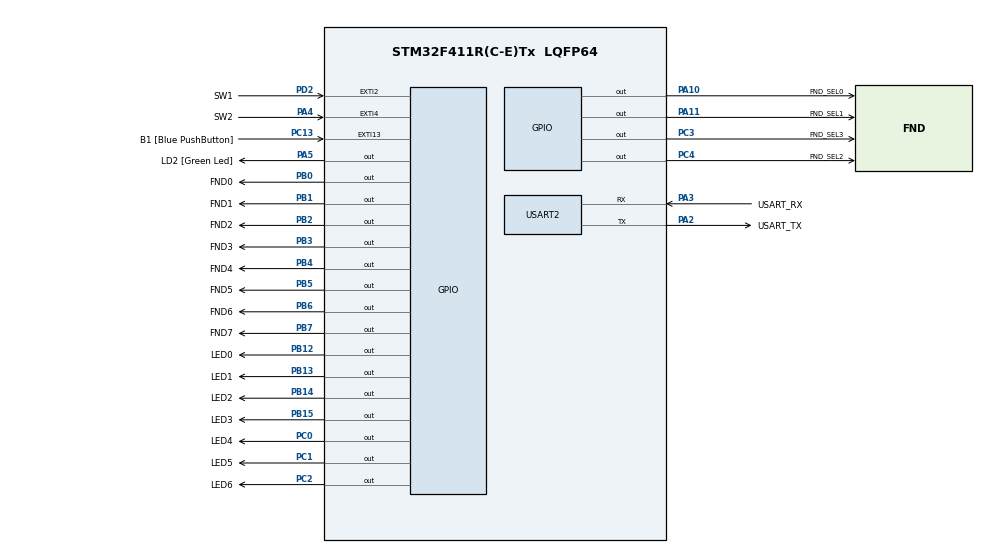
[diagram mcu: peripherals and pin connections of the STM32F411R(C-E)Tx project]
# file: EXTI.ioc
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Mcu.Family=STM32F4
Mcu.Name=STM32F411R(C-E)Tx
Mcu.Package=LQFP64
NVIC.EXTI15_10_IRQn=true\:0\:0\:false\:false\:true\:true\:true\:true
NVIC.EXTI2_IRQn=true\:0\:0\:false\:false\:true\:true\:true\:true
NVIC.EXTI4_IRQn=true\:0\:0\:false\:false\:true\:true\:true\:true
NVIC.PriorityGroup=NVIC_PRIORITYGROUP_0
PA10.GPIO_Label=FND_SEL0
PA10.Signal=GPIO_Output
PA11.GPIO_Label=FND_SEL1
PA11.Signal=GPIO_Output
PA13.GPIO_Label=TMS
PA13.Mode=Serial_Wire
PA13.Signal=SYS_JTMS-SWDIO
PA14.GPIO_Label=TCK
PA14.Mode=Serial_Wire
PA14.Signal=SYS_JTCK-SWCLK
PA2.GPIO_Label=USART_TX
PA2.Mode=Asynchronous
PA2.Signal=USART2_TX
PA3.GPIO_Label=USART_RX
PA3.Mode=Asynchronous
PA3.Signal=USART2_RX
PA4.GPIO_Label=SW2
PA4.Signal=GPXTI4
PA5.GPIO_Label=LD2 [Green Led]
PA5.Signal=GPIO_Output
PB0.GPIO_Label=FND0
PB0.Signal=GPIO_Output
PB1.GPIO_Label=FND1
PB1.Signal=GPIO_Output
PB12.GPIO_Label=LED0
PB12.Signal=GPIO_Output
PB13.GPIO_Label=LED1
PB13.Signal=GPIO_Output
PB14.GPIO_Label=LED2
PB14.Signal=GPIO_Output
PB15.GPIO_Label=LED3
PB15.Signal=GPIO_Output
PB2.GPIO_Label=FND2
PB2.Signal=GPIO_Output
PB3.GPIO_Label=FND3
PB3.Signal=GPIO_Output
PB4.GPIO_Label=FND4
PB4.Signal=GPIO_Output
PB5.GPIO_Label=FND5
PB5.Signal=GPIO_Output
PB6.GPIO_Label=FND6
PB6.Signal=GPIO_Output
PB7.GPIO_Label=FND7
PB7.Signal=GPIO_Output
PC0.GPIO_Label=LED4
PC0.Signal=GPIO_Output
PC1.GPIO_Label=LED5
PC1.Signal=GPIO_Output
PC13-ANTI_TAMP.GPIO_Label=B1 [Blue PushButton]
PC13-ANTI_TAMP.GPIO_ModeDefaultEXTI=GPIO_MODE_IT_RISING_FALLING
PC13-ANTI_TAMP.Signal=GPXTI13
PC14-OSC32_IN.Signal=RCC_OSC32_IN
PC15-OSC32_OUT.Signal=RCC_OSC32_OUT
PC2.GPIO_Label=LED6
PC2.Signal=GPIO_Output
PC3.GPIO_Label=FND_SEL3
PC3.Signal=GPIO_Output
PC4.GPIO_Label=FND_SEL2
PC4.Signal=GPIO_Output
PD2.GPIO_Label=SW1
PD2.GPIO_ModeDefaultEXTI=GPIO_MODE_IT_RISING_FALLING
PD2.Signal=GPXTI2
PH0\ -\ OSC_IN.Signal=RCC_OSC_IN
PH1\ -\ OSC_OUT.Signal=RCC_OSC_OUT
ProjectManager.HeapSize=0x200
ProjectManager.StackSize=0x400
ProjectManager.TargetToolchain=STM32CubeIDE
RCC.48MHZClocksFreq_Value=32000000
RCC.AHBFreq_Value=64000000
RCC.APB1CLKDivider=RCC_HCLK_DIV2
RCC.APB1Freq_Value=32000000
RCC.APB1TimFreq_Value=64000000
RCC.APB2Freq_Value=64000000
RCC.APB2TimFreq_Value=64000000
RCC.CortexFreq_Value=64000000
RCC.FLatency-AdvancedSettings=FLASH_LATENCY_2
RCC.HCLKFreq_Value=64000000
RCC.HSE_VALUE=8000000
RCC.HSI_VALUE=16000000
RCC.PLLM=8
RCC.PLLN=64
RCC.SYSCLKFreq_VALUE=64000000
RCC.SYSCLKSource=RCC_SYSCLKSOURCE_PLLCLK
RCC.VCOOutputFreq_Value=128000000
USART2.VirtualMode=VM_ASYNC
board=NUCLEO-F411RE

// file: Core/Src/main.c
/* USER CODE BEGIN Header */
/**
  ******************************************************************************
  * @file           : main.c
  * @brief          : Main program body
  ******************************************************************************
  * @attention
  *
  * Copyright (c) 2023 STMicroelectronics.
  * All rights reserved.
  *
  * This software is licensed under terms that can be found in the LICENSE file
  * in the root directory of this software component.
  * If no LICENSE file comes with this software, it is provided AS-IS.
  *
  ******************************************************************************
  */
/* USER CODE END Header */
#include "main.h"

UART_HandleTypeDef huart2;

/* USER CODE BEGIN PV */
int i=0, icnt, SW1Flag, SW2Flag;
uint16_t data[4] = {1,2,3,4}, _digit=0;

/* USER CODE END PV */

void SystemClock_Config(void);
static void MX_GPIO_Init(void);
static void MX_USART2_UART_Init(void);
/* USER CODE BEGIN PFP */
void Seg_Reset(void);
void Seg_Number(uint16_t val, uint8_t dp);
/* USER CODE END PFP */

int main(void)
{

  /* MCU Configuration--------------------------------------------------------*/

  /* Reset of all peripherals, Initializes the Flash interface and the Systick. */
  HAL_Init();

  /* Configure the system clock */
  SystemClock_Config();

  /* Initialize all configured peripherals */
  MX_GPIO_Init();
  MX_USART2_UART_Init();

  /* Infinite loop */
  /* USER CODE BEGIN WHILE */
  icnt=0;

  SW1Flag=0;
  SW2Flag=0;

  _digit=0;
  Seg_Reset();

  while (1)
  {

     HAL_GPIO_WritePin(GPIOA, FND_SEL0_Pin, GPIO_PIN_SET);

  if( _digit == 0)

     Seg_Number(data[0],1);

  else

     Seg_Number(data[0],0);

  HAL_Delay(5);

  HAL_GPIO_WritePin(GPIOA, FND_SEL0_Pin, GPIO_PIN_RESET);

  HAL_GPIO_WritePin(GPIOA, FND_SEL1_Pin, GPIO_PIN_SET);

  if( _digit == 1)

     Seg_Number(data[1],1);

  else

       Seg_Number(data[1],0);

  HAL_Delay(5);

  HAL_GPIO_WritePin(GPIOA, FND_SEL1_Pin, GPIO_PIN_RESET);

  HAL_GPIO_WritePin(GPIOC, FND_SEL2_Pin, GPIO_PIN_SET);

  if( _digit == 2)

     Seg_Number(data[2],1);

  else

       Seg_Number(data[2],0);

  HAL_Delay(5);

  HAL_GPIO_WritePin(GPIOC, FND_SEL2_Pin, GPIO_PIN_RESET);

  HAL_GPIO_WritePin(GPIOC, FND_SEL3_Pin, GPIO_PIN_SET);

  if( _digit == 3)

        Seg_Number(data[3],1);

     else

          Seg_Number(data[3],0);

       HAL_Delay(5);

       HAL_GPIO_WritePin(GPIOC, FND_SEL3_Pin, GPIO_PIN_RESET);

     if( SW1Flag ){

              SW1Flag=0;

              data[_digit]++;

              data[_digit] %= 10;

           }

           if(SW2Flag){

              SW2Flag=0;

              _digit++;

              _digit %= 4;

           }
    /* USER CODE END WHILE */

  }
}

void SystemClock_Config(void)
{
  RCC_OscInitTypeDef RCC_OscInitStruct = {0};
  RCC_ClkInitTypeDef RCC_ClkInitStruct = {0};

  /** Configure the main internal regulator output voltage
  */
  __HAL_RCC_PWR_CLK_ENABLE();
  __HAL_PWR_VOLTAGESCALING_CONFIG(PWR_REGULATOR_VOLTAGE_SCALE1);

  /** Initializes the RCC Oscillators according to the specified parameters
  * in the RCC_OscInitTypeDef structure.
  */
  RCC_OscInitStruct.OscillatorType = RCC_OSCILLATORTYPE_HSI;
  RCC_OscInitStruct.HSIState = RCC_HSI_ON;
  RCC_OscInitStruct.HSICalibrationValue = RCC_HSICALIBRATION_DEFAULT;
  RCC_OscInitStruct.PLL.PLLState = RCC_PLL_ON;
  RCC_OscInitStruct.PLL.PLLSource = RCC_PLLSOURCE_HSI;
  RCC_OscInitStruct.PLL.PLLM = 16;
  RCC_OscInitStruct.PLL.PLLN = 336;
  RCC_OscInitStruct.PLL.PLLP = RCC_PLLP_DIV4;
  RCC_OscInitStruct.PLL.PLLQ = 4;
  if (HAL_RCC_OscConfig(&RCC_OscInitStruct) != HAL_OK)
  {
    Error_Handler();
  }

  /** Initializes the CPU, AHB and APB buses clocks
  */
  RCC_ClkInitStruct.ClockType = RCC_CLOCKTYPE_HCLK|RCC_CLOCKTYPE_SYSCLK
                              |RCC_CLOCKTYPE_PCLK1|RCC_CLOCKTYPE_PCLK2;
  RCC_ClkInitStruct.SYSCLKSource = RCC_SYSCLKSOURCE_PLLCLK;
  RCC_ClkInitStruct.AHBCLKDivider = RCC_SYSCLK_DIV1;
  RCC_ClkInitStruct.APB1CLKDivider = RCC_HCLK_DIV2;
  RCC_ClkInitStruct.APB2CLKDivider = RCC_HCLK_DIV1;

  if (HAL_RCC_ClockConfig(&RCC_ClkInitStruct, FLASH_LATENCY_2) != HAL_OK)
  {
    Error_Handler();
  }
}

static void MX_USART2_UART_Init(void)
{

  huart2.Instance = USART2;
  huart2.Init.BaudRate = 115200;
  huart2.Init.WordLength = UART_WORDLENGTH_8B;
  huart2.Init.StopBits = UART_STOPBITS_1;
  huart2.Init.Parity = UART_PARITY_NONE;
  huart2.Init.Mode = UART_MODE_TX_RX;
  huart2.Init.HwFlowCtl = UART_HWCONTROL_NONE;
  huart2.Init.OverSampling = UART_OVERSAMPLING_16;
  if (HAL_UART_Init(&huart2) != HAL_OK)
  {
    Error_Handler();
  }

}

static void MX_GPIO_Init(void)
{
  GPIO_InitTypeDef GPIO_InitStruct = {0};

  /* GPIO Ports Clock Enable */
  __HAL_RCC_GPIOC_CLK_ENABLE();
  __HAL_RCC_GPIOH_CLK_ENABLE();
  __HAL_RCC_GPIOA_CLK_ENABLE();
  __HAL_RCC_GPIOB_CLK_ENABLE();
  __HAL_RCC_GPIOD_CLK_ENABLE();

  /*Configure GPIO pin Output Level */
  HAL_GPIO_WritePin(GPIOC, LED4_Pin|LED5_Pin|LED6_Pin|FND_SEL3_Pin
                          |FND_SEL2_Pin, GPIO_PIN_RESET);

  /*Configure GPIO pin Output Level */
  HAL_GPIO_WritePin(GPIOA, LD2_Pin|FND_SEL0_Pin|FND_SEL1_Pin, GPIO_PIN_RESET);

  /*Configure GPIO pin Output Level */
  HAL_GPIO_WritePin(GPIOB, FND0_Pin|FND1_Pin|FND2_Pin|LED0_Pin
                          |LED1_Pin|LED2_Pin|LED3_Pin|FND3_Pin
                          |FND4_Pin|FND5_Pin|FND6_Pin|FND7_Pin, GPIO_PIN_RESET);

  /*Configure GPIO pin : B1_Pin */
  GPIO_InitStruct.Pin = B1_Pin;
  GPIO_InitStruct.Mode = GPIO_MODE_IT_FALLING;
  GPIO_InitStruct.Pull = GPIO_NOPULL;
  HAL_GPIO_Init(B1_GPIO_Port, &GPIO_InitStruct);

  /*Configure GPIO pins : LED4_Pin LED5_Pin LED6_Pin FND_SEL3_Pin
                           FND_SEL2_Pin */
  GPIO_InitStruct.Pin = LED4_Pin|LED5_Pin|LED6_Pin|FND_SEL3_Pin
                          |FND_SEL2_Pin;
  GPIO_InitStruct.Mode = GPIO_MODE_OUTPUT_PP;
  GPIO_InitStruct.Pull = GPIO_NOPULL;
  GPIO_InitStruct.Speed = GPIO_SPEED_FREQ_LOW;
  HAL_GPIO_Init(GPIOC, &GPIO_InitStruct);

  /*Configure GPIO pin : SW2_Pin */
  GPIO_InitStruct.Pin = SW2_Pin;
  GPIO_InitStruct.Mode = GPIO_MODE_IT_RISING;
  GPIO_InitStruct.Pull = GPIO_NOPULL;
  HAL_GPIO_Init(SW2_GPIO_Port, &GPIO_InitStruct);

  /*Configure GPIO pins : LD2_Pin FND_SEL0_Pin FND_SEL1_Pin */
  GPIO_InitStruct.Pin = LD2_Pin|FND_SEL0_Pin|FND_SEL1_Pin;
  GPIO_InitStruct.Mode = GPIO_MODE_OUTPUT_PP;
  GPIO_InitStruct.Pull = GPIO_NOPULL;
  GPIO_InitStruct.Speed = GPIO_SPEED_FREQ_LOW;
  HAL_GPIO_Init(GPIOA, &GPIO_InitStruct);

  /*Configure GPIO pins : FND0_Pin FND1_Pin FND2_Pin LED0_Pin
                           LED1_Pin LED2_Pin LED3_Pin FND3_Pin
                           FND4_Pin FND5_Pin FND6_Pin FND7_Pin */
  GPIO_InitStruct.Pin = FND0_Pin|FND1_Pin|FND2_Pin|LED0_Pin
                          |LED1_Pin|LED2_Pin|LED3_Pin|FND3_Pin
                          |FND4_Pin|FND5_Pin|FND6_Pin|FND7_Pin;
  GPIO_InitStruct.Mode = GPIO_MODE_OUTPUT_PP;
  GPIO_InitStruct.Pull = GPIO_NOPULL;
  GPIO_InitStruct.Speed = GPIO_SPEED_FREQ_LOW;
  HAL_GPIO_Init(GPIOB, &GPIO_InitStruct);

  /*Configure GPIO pin : SW1_Pin */
  GPIO_InitStruct.Pin = SW1_Pin;
  GPIO_InitStruct.Mode = GPIO_MODE_IT_RISING;
  GPIO_InitStruct.Pull = GPIO_NOPULL;
  HAL_GPIO_Init(SW1_GPIO_Port, &GPIO_InitStruct);

  /* EXTI interrupt init*/
  HAL_NVIC_SetPriority(EXTI2_IRQn, 0, 0);
  HAL_NVIC_EnableIRQ(EXTI2_IRQn);

  HAL_NVIC_SetPriority(EXTI4_IRQn, 0, 0);
  HAL_NVIC_EnableIRQ(EXTI4_IRQn);

  HAL_NVIC_SetPriority(EXTI15_10_IRQn, 0, 0);
  HAL_NVIC_EnableIRQ(EXTI15_10_IRQn);

}

/* USER CODE BEGIN 4 */
void Seg_Reset( void ){

   HAL_GPIO_WritePin(GPIOB, FND0_Pin|FND1_Pin|FND2_Pin|FND3_Pin

           |FND4_Pin|FND5_Pin|FND6_Pin|FND7_Pin, GPIO_PIN_RESET);

}

void Seg_Number( uint16_t val, uint8_t dp){

   uint16_t _bits;

   _bits = FND0_Pin|FND1_Pin|FND2_Pin|FND3_Pin|FND4_Pin|FND5_Pin;  // "0"

   // Clear All segment port bits...

   HAL_GPIO_WritePin(GPIOB, FND0_Pin|FND1_Pin|FND2_Pin|FND3_Pin

              |FND4_Pin|FND5_Pin|FND6_Pin|FND7_Pin, GPIO_PIN_RESET);

   switch(val%10){

      case 1:

         _bits = FND1_Pin|FND2_Pin;

         break;

      case 2:

         _bits = FND0_Pin|FND1_Pin|FND3_Pin|FND4_Pin|FND6_Pin;

         break;

      case 3:

         _bits = FND0_Pin|FND1_Pin|FND2_Pin|FND3_Pin|FND6_Pin;

         break;

      case 4:

         _bits = FND1_Pin|FND2_Pin|FND5_Pin|FND6_Pin;

         break;

      case 5:

         _bits = FND0_Pin|FND2_Pin|FND3_Pin|FND5_Pin|FND6_Pin;

         break;

      case 6:

         _bits = FND2_Pin|FND3_Pin|FND4_Pin|FND5_Pin|FND6_Pin;

         break;

      case 7:

         _bits = FND0_Pin|FND1_Pin|FND2_Pin;

         break;

      case 8:

         _bits = FND0_Pin|FND1_Pin|FND2_Pin|FND3_Pin|FND4_Pin|FND5_Pin|FND6_Pin;

         break;

      case 9:

         _bits = FND0_Pin|FND1_Pin|FND2_Pin|FND5_Pin|FND6_Pin;

         break;

   }

   if(dp)

      _bits |= FND7_Pin;

   HAL_GPIO_WritePin(GPIOB, _bits, GPIO_PIN_SET);
}

   void HAL_GPIO_EXTI_Callback(uint16_t GPIO_Pin){

      icnt++;

      if(GPIO_Pin == SW1_Pin){

         SW1Flag = 1;

         SW2Flag = 0;

      }else if(GPIO_Pin == SW2_Pin){

         SW1Flag = 0;

         SW2Flag = 1;

      }

   }

/* USER CODE END 4 */

void Error_Handler(void)
{
  __disable_irq();
  while (1)
  {
  }
}
